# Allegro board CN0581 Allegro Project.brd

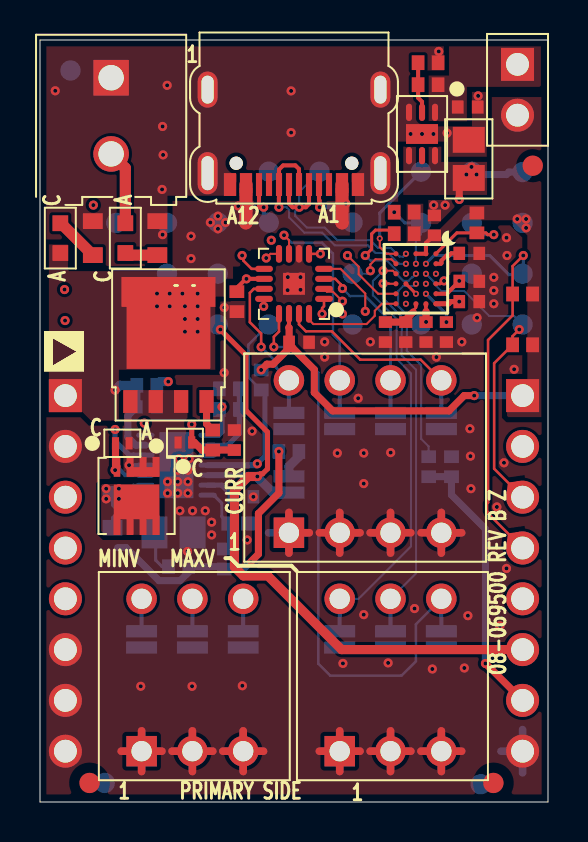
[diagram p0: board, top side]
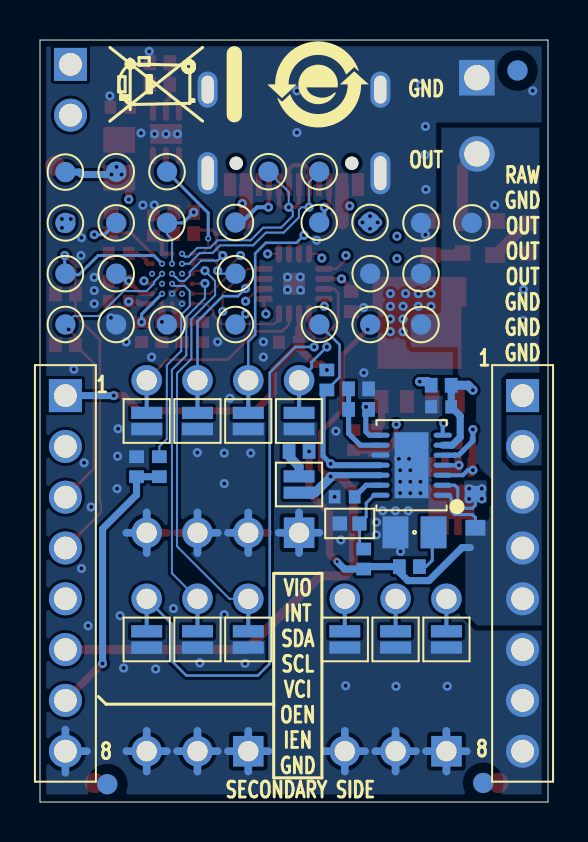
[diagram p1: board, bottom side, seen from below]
Outline 25.4 x 38.1 mm; copper layers: TOP, L2_GND, L3_SIG/PWR, BOTTOM. Coordinates in mm from the lower left corner of the outline.
Outline path: 0,38.1 0,0 25.4,0 25.4,38.1 0,38.1

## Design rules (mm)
constraint set DEFAULT: min track width 0.102

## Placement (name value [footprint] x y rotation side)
C1  100NF  [C0402]  5.34 19.76 180 bottom
C2  0.022uF  [C0402]  10.17 15.26 180 bottom
C3  4.7uF  [C0805H53]  21.44 32.16 90 top
C4  1uF  [C0402]  12.95 22.99 0 top
C5  6800pF  [C0402]  9.72 18.1 270 top
C6  4.7uF  [C0402]  21.39 34.75 180 top
C7  1uF  [C0402]  17.27 23.49 270 top
C8  1uF  [C0402]  18.29 23.49 270 top
C9  1uF  [C0402]  20.32 23.49 270 top
C10  1uF  [C0402]  21.46 27.43 0 top
C11  1uF  [C0402]  21.46 26.04 0 top
C12  22uF  [C0805H60]  6.68 13.48 180 bottom
C13  0.1UF  [C0402]  21.46 25.02 0 top
C15  0.1UF  [C0402]  19.3 23.49 270 top
C16  1uF  [C0402]  19.72 28.83 90 top
D1  BZT52B15LP-7B  [DFN2_1X0_6]  7.25 17.98 180 top
D2  BZT52B15LP-7B  [DFN2_1X0_6]  4.12 17.93 0 top
DS1  LTST-C193KGKT-5A  [LED0603H12]  1.02 28.19 270 top
DS2  LTST-C193KGKT-5A  [LED0603H12]  4.27 28.19 90 top
M1  12402012E212A  [M12402012E212A]  12.7 34.54 180 top
NOREF  -  []  11.43 85.73 0 top
NOREF#2  -  [unnamed#2]  2.48 0.95 0 top
NOREF#3  -  []  92.71 68.58 0 top
NOREF#4  -  []  25.4 0 90 top
NOREF#5  -  []  1.27 2.54 0 top
NOREF#6  -  []  -159.89 -89.83 0 top
NOREF#7  -  []  0 0 0 top
NOREF#8  -  []  -160.27 -77.77 0 top
NOREF#9  -  []  -164.71 -81.39 0 top
NOREF#10  -  [unnamed#2]  24.64 31.81 0 top
NOREF#11  -  []  0 38.1 0 top
NOREF#12  -  []  -153.98 -76.88 0 top
NOREF#13  -  []  0 0 0 top
NOREF#14  -  []  25.4 0 90 top
NOREF#15  -  []  0 38.1 0 top
NOREF#16  -  []  1.27 2.54 0 top
NOREF#17  -  [unnamed#2]  22.67 0.95 0 top
NOREF#18  -  []  -222.25 -146.05 0 top
NOREF#19  -  []  0 38.1 270 top
NOREF#20  -  []  25.4 0 0 top
NOREF#21  -  []  0 0 0 top
NOREF#22  -  []  25.4 38.1 180 top
NOREF#23  -  [unnamed#2]  22.03 0.89 180 bottom
NOREF#24  -  [unnamed#2]  3.24 0.95 180 bottom
NOREF#25  -  []  11.49 35.88 180 bottom
NOREF#26  -  []  15.37 35.69 90 bottom
NOREF#27  -  [unnamed#2]  1.52 36.58 180 bottom
P1  -  [JPSLD02]  5.08 8.13 90 bottom
P2  -  [JPSLD02]  7.62 8.13 90 bottom
P3  -  [JPSLD02]  10.16 8.13 90 bottom
P4  -  [JPSLD02]  14.99 8.13 90 bottom
P5  -  [JPSLD02]  17.53 8.13 90 bottom
P6  -  [JPSLD02]  20.07 8.13 90 bottom
P7  -  [JPSLD02]  12.45 19.05 90 bottom
P8  -  [JPSLD02]  14.99 19.05 90 bottom
P9  -  [JPSLD02]  17.53 19.05 90 bottom
P10  -  [JPSLD02]  20.07 19.05 90 bottom
P11  CTB0308/2  [CNCAMDENCTB0308_2]  3.56 36.21 270 top
P12  M20-9990846  [CNHDR1X8H335]  1.27 20.32 270 bottom
P13  -  [JPSLD02]  12.45 15.88 90 bottom
P14  M20-9990846  [CNHDR1X8H335]  24.13 20.32 270 bottom
P15  TSW-101-08-F-D  [CNHDR2X1H340]  23.88 36.88 180 top
Q1  PSMN4R2-80YSEX  [SOT1023]  6.42 22.75 0 top
Q2  BSZ019N03LSATMA1  [PG-TSDSON-8_A]  4.83 15.3 180 top
R1  2.15K  [R0402]  19.43 16.76 90 bottom
R2  49.9K  [R0402]  20.57 16.76 270 bottom
R3  124K  [R0402]  5.34 20.84 180 bottom
R4  57.6K  [R0402]  9.47 19.63 180 bottom
R5  0  [R0402]  19.41 35.86 180 top
R6  1.5K  [R0603]  2.64 28.19 90 top
R7  2.15K  [R0402]  19.41 36.97 180 top
R8  49.9K  [R0402]  9.84 25.02 90 top
R9  2.15K  [R0402]  24.13 25.4 0 top
R10  2.15K  [R0402]  24.13 22.86 0 top
R11  2.15K  [R0402]  18.21 29.49 0 top
R12  2.15K  [R0402]  18.21 28.41 0 top
R13  49.9K  [R0402]  21.84 28.96 90 top
R14  11K  [R0402]  9.47 20.66 0 bottom
R15  1.5K  [R0603]  5.87 28.19 90 top
R16  10  [R0402]  8.64 18.1 270 top
R17  100K  [R0402]  11.06 21.1 90 bottom
R18  95.3K  [R0402]  9.22 12.15 270 bottom
R19  5K  [R0402H33]  9.91 13.93 180 bottom
R20  0.007  [R0603]  3.63 14.56 270 bottom
R21  100K  [R0402]  12.45 17.53 180 bottom
R22  0.1  [R0402]  6.93 11.77 0 bottom
S1  DS01C-254-S-03BE  [SWTHL356W390H281]  5.08 2.54 0 top
S2  DS01C-254-S-03BE  [SWTHL356W390H281]  14.99 2.54 0 top
S3  DS01C-254-L-04BE  [SWTHL456W390H281]  12.45 13.46 0 top
TP1  TESTPAD  [TPSMC40]  24.13 31.5 180 bottom
TP2  TESTPAD  [TPSMC40]  8.9 28.98 180 bottom
TP3  TESTPAD  [TPSMC40]  6.35 23.88 180 bottom
TP4  TESTPAD  [TPSMC40]  3.81 28.96 180 bottom
TP5  TESTPAD  [TPSMC40]  15.63 28.98 180 bottom
TP6  TESTPAD  [TPSMC40]  11.44 28.98 180 bottom
TP7  TESTPAD  [TPSMC40]  13.98 31.52 180 bottom
TP8  TESTPAD  [TPSMC40]  11.44 31.52 180 bottom
TP9  TESTPAD  [TPSMC40]  6.35 26.42 180 bottom
TP10  TESTPAD  [TPSMC40]  6.35 28.96 180 bottom
TP11  TESTPAD  [TPSMC40]  8.89 26.42 180 bottom
TP12  TESTPAD  [TPSMC40]  21.59 31.52 180 bottom
TP13  TESTPAD  [TPSMC40]  24.13 28.96 180 bottom
TP14  TESTPAD  [TPSMC40]  24.13 26.42 180 bottom
TP15  TESTPAD  [TPSMC40]  24.13 23.88 180 bottom
TP16  TESTPAD  [TPSMC40]  21.59 26.42 180 bottom
TP17  TESTPAD  [TPSMC40]  21.59 28.96 180 bottom
TP18  TESTPAD  [TPSMC40]  21.59 23.88 180 bottom
TP19  TESTPAD  [TPSMC40]  8.89 23.88 180 bottom
TP20  TESTPAD  [TPSMC40]  11.43 23.88 180 bottom
TP21  TESTPAD  [TPSMC40]  19.05 31.52 180 bottom
TP22  TESTPAD  [TPSMC40]  15.63 26.42 180 bottom
TP23  TESTPAD  [TPSMC40]  19.05 28.96 180 bottom
TP24  TESTPAD  [TPSMC40]  15.63 23.88 180 bottom
TP25  TESTPAD  [TPSMC40]  19.05 23.88 180 bottom
U1  LTC4364HDE-2#PBF  [DFN14_4X3_PAD3_3X1_7]  6.82 16.84 90 bottom
U2  ADP7142ACPZN3.3  [DFN6_2X2_PAD1_6X1]  19.1 33.4 180 top
U3  MAX4701ETE+  [QFN16_3X3_PAD1_1X1_1]  12.7 25.91 90 top
U4  MAX77958EWV+  [WLCSP30H27]  18.8 26.16 180 top

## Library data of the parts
C1 = CAP: User Part Number: UPN; Tolerance: 10; alternate symbols: (C0402L); part number: CAP_SM-100NF,25V,10,E060176,C0402; tolerance: 10
C2 = CAP: User Part Number: UPN; Tolerance: 10; alternate symbols: (C0402L); part number: CAP_SM-0.022UF,25V,10,E042115,C0402; tolerance: 10
C3 = CAP: Tolerance: 10; User Part Number: UPN; alternate symbols: (); part number: CAP_SM-4.7UF,50V,10,E028468,C0805H53; tolerance: 10
C4 C7-C11 C16 = CAP: User Part Number: UPN; Tolerance: 10; alternate symbols: (C0402L); part number: CAP_SM-1UF,10V,10,E028140,C0402; tolerance: 10
C5 = CAP: User Part Number: UPN; Tolerance: 10; alternate symbols: (C0402L); part number: CAP_SM-6800PF,50V,10,E034944,C0402; tolerance: 10
C6 = CAP: User Part Number: UPN; Tolerance: 10; alternate symbols: (C0402L); part number: CAP_SM-4.7UF,6.3V,10,E020089,C0402; tolerance: 10
C12 = CAP: Tolerance: 20; User Part Number: UPN; alternate symbols: (); part number: CAP_SM-22UF,35V,20,E025497,C0805H60; tolerance: 20
C13 C15 = CAP: User Part Number: UPN; Tolerance: 10; alternate symbols: (C0402L); part number: CAP_SM-0.1UF,50V,10,E048331,C0402; tolerance: 10
D1 D2 = DIOZNR: Tolerance: 2; User Part Number: UPN; alternate symbols: (); part number: DIOZNR_SM-BZT52B15LP-7B,15V,2,E061558,DFN2_1X0_6; tolerance: 2
DS1 DS2 = DIOLED: User Part Number: UPN; Tolerance: N/A; alternate symbols: (); part number: DIOLED_SM-LTST-C193KGKT-5A,N/A,N/A,E020972,LED0603H12; tolerance: N/A
M1 = MODUSB16P_4PSHLD_V2: User Part Number: UPN; Tolerance: N/A; alternate symbols: (); part number: MODUSB16P_4PSHLD_V2_SM-12402012E212A,E055749,M12402012E212A; tolerance: N/A
P1-P10 P13 = NC2P: User Part Number: UPN; Tolerance: N/A; alternate symbols: (); part number: NC2P_SM-JPSLD02,E006230,JPSLD02; tolerance: N/A
P11 = CN2P: User Part Number: UPN; Tolerance: N/A; alternate symbols: (); part number: CN2P_TH-CTB0308/2,E026049,CNCAMDENCTB0308_2; tolerance: N/A
P12 P14 = CN8P_A: User Part Number: UPN; Tolerance: N/A; alternate symbols: (); part number: CN8P_A_TH-M20-9990846,E027673,CNHDR1X8H335; tolerance: N/A
P15 = CN2P: User Part Number: UPN; Tolerance: N/A; alternate symbols: (); part number: CN2P_TH-TSW-101-08-F-D,E023119,CNHDR2X1H340; tolerance: N/A
Q1 = TRANNMOSFET_V13: Tolerance: N/A; User Part Number: UPN; alternate symbols: (); part number: TRANNMOSFET_V13_SM-PSMN4R2-80YSEX,E061557,SOT1023; tolerance: N/A
Q2 = TRANNMOSFET8P: User Part Number: UPN; Tolerance: N/A; alternate symbols: (); part number: TRANNMOSFET8P_SM-BSZ019N03LSATMA1,E026048,PG-TSDSON-8_A; tolerance: N/A
R1 R7 R9-R12 = RES: User Part Number: UPN; Tolerance: 1; alternate symbols: (R0402L); part number: RES_SM-2.15K,E030383,1/10W,1,R0402; tolerance: 1
R2 R8 R13 = RES: User Part Number: UPN; Tolerance: 1; alternate symbols: (R0402L); part number: RES_SM-49.9K,E026957,1/16W,1,R0402; tolerance: 1
R3 = RES: User Part Number: UPN; Tolerance: 1; alternate symbols: (R0402L); part number: RES_SM-124K,E026070,1/16W,1,R0402; tolerance: 1
R4 = RES: User Part Number: UPN; Tolerance: 1; alternate symbols: (R0402L); part number: RES_SM-57.6K,E022063,1/16W,1,R0402; tolerance: 1
R5 = RES: User Part Number: UPN; Tolerance: JUMPER; alternate symbols: (R0402L); part number: RES_SM-0,E025232,1/16W,JUMPER,R0402; tolerance: JUMPER
R6 R15 = RES: User Part Number: UPN; Tolerance: 5; alternate symbols: (R0603L); part number: RES_SM-1.5K,E056769,1/4W,5,R0603; tolerance: 5
R14 = RES: User Part Number: UPN; Tolerance: 1; alternate symbols: (R0402L); part number: RES_SM-11K,E015614,1/10W,1,R0402; tolerance: 1
R16 = RES: User Part Number: UPN; Tolerance: 5; alternate symbols: (R0402L); part number: RES_SM-10,E042731,1/10W,5,R0402; tolerance: 5
R17 R21 = RES: User Part Number: UPN; Tolerance: 5; alternate symbols: (R0402L); part number: RES_SM-100K,E027220,1/16W,5,R0402; tolerance: 5
R18 = RES: User Part Number: UPN; Tolerance: 1; alternate symbols: (R0402L); part number: RES_SM-95.3K,E006343,1/10W,1,R0402; tolerance: 1
R19 = RES: Tolerance: 0.1; User Part Number: UPN; alternate symbols: (); part number: RES_SM-5K,E025964,1/20W,0.1,R0402H33; tolerance: 0.1
R20 = RES: User Part Number: UPN; Tolerance: 1; alternate symbols: (R0603L); part number: RES_SM-0.007,E061842,1/2W,1,R0603; tolerance: 1
R22 = RES: User Part Number: UPN; Tolerance: 1; alternate symbols: (R0402L); part number: RES_SM-0.1,E017078,1/6W,1,R0402; tolerance: 1
S1 S2 = SWSPST6PIN: User Part Number: UPN; Tolerance: N/A; alternate symbols: (); part number: SWSPST6PIN_TH-DS01C-254-S-03BE,E055746,SWTHL356W390H281; tolerance: N/A
S3 = SWSPST8P: User Part Number: UPN; Tolerance: N/A; alternate symbols: (); part number: SWSPST8P_TH-DS01C-254-L-04BE,E055747,SWTHL456W390H281; tolerance: N/A
TP1-TP25 = NCTESTPAD: Tolerance: N/A; User Part Number: UPN; alternate symbols: (); part number: NCTESTPAD_SM-TESTPAD,E019801,TPSMC40; tolerance: N/A
U1 = LINLTC4364_X: User Part Number: UPN; Tolerance: N/A; alternate symbols: (); part number: LINLTC4364_X_SM-LTC4364HDE-2#PBF,E031515,DFN14_4X3_PAD3_3X1_7; tolerance: N/A
U2 = ADP7142: User Part Number: UPN; Tolerance: N/A; alternate symbols: (); part number: ADP7142_SM-ADP7142ACPZN3.3,E023518,DFN6_2X2_PAD1_6X1; tolerance: N/A
U3 = ADMAX4XXX: User Part Number: UPN; Tolerance: N/A; alternate symbols: (); part number: ADMAX4XXX_SM-MAX4701ETE+,E055643,QFN16_3X3_PAD1_1X1_1; tolerance: N/A
U4 = ICMAX77958: User Part Number: UPN; Tolerance: N/A; alternate symbols: (); part number: ICMAX77958_SM-MAX77958EWV+,E045058,WLCSP30H27; tolerance: N/A

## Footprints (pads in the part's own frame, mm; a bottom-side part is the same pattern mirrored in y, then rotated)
C0402
  rect 0.584x0.66 smd: 1(-0.5,0) 2(0.5,0)
C0805H53
  rect 1.295x1.6 smd: 1(-0.953,0) 2(0.953,0)
C0805H60
  rect 1.295x1.6 smd: 1(-0.953,0) 2(0.953,0)
CNCAMDENCTB0308_2
  rect 1.778x1.778 hole 1.27: 1(0,0)
  round 1.778 hole 1.27: 2(3.81,0)
CNHDR1X8H335
  rect 1.651x1.651 hole 1.143: 1(0,0)
  round 1.651 hole 1.143: 2(2.54,0) 3(5.08,0) 4(7.62,0) 5(10.16,0) 6(12.7,0) 7(15.24,0) 8(17.78,0)
CNHDR2X1H340
  rect 1.651x1.651 hole 1.143: 1(0,0)
  round 1.651 hole 1.143: 2(0,2.54)
DFN2_1X0_6
  rect 0.356x0.61 smd: A(0.34,0) C(-0.34,0)
DFN6_2X2_PAD1_6X1
  oval 0.305x0.864 smd: 1(-0.65,-1.082) 2(0,-1.082) 3(0.65,-1.082) 4(0.65,1.082) 5(0,1.082) 6(-0.65,1.082)
  rect 1.6x0.991 smd: PAD(0,0)
DFN14_4X3_PAD3_3X1_7
  oval 0.254x0.914 smd: 1(-1.5,-1.557) 2(-1,-1.557) 3(-0.5,-1.557) 4(0,-1.557) 5(0.5,-1.557) 6(1,-1.557) 7(1.5,-1.557) 8(1.5,1.557) 9(1,1.557) 10(0.5,1.557) 11(0,1.557) 12(-0.5,1.557) 13(-1,1.557) 14(-1.5,1.557)
  rect 3.302x1.702 smd: PAD(0,0)
JPSLD02
  rect 0.61x1.549 smd: 1(-0.406,0) 2(0.406,0)
LED0603H12
  rect 0.787x0.787 smd: A(0.744,0) C(-0.744,0)
M12402012E212A
  round 0.66 hole 0.66 unplated: (-2.89,2.605) (2.89,2.605)
  rect 0.61x1.143 smd: A1(-3.2,3.67) A4(-2.4,3.67) A9(2.4,3.67) A12(3.2,3.67)
  rect 0.305x1.143 smd: A5(-1.25,3.67) A6(-0.25,3.67) A7(0.25,3.67) A8(1.25,3.67) B5(1.75,3.67) B6(0.75,3.67) B7(-0.75,3.67) B8(-1.75,3.67)
  round 0.127 smd: B1(3.2,3.97) B4(2.4,3.97) B9(-2.4,3.97) B12(-3.2,3.97)
  oval 0.991x2.108 hole 0.61x1.702: SH1(-4.32,3.105) SH4(4.32,3.105)
  oval 0.991x1.803 hole 0.61x1.397: SH2(-4.32,-1.075) SH3(4.32,-1.075)
PG-TSDSON-8_A
  rect 0.33x0.991 smd: 1(-0.975,-1.455) 2(-0.325,-1.455) 3(0.325,-1.455) 4(0.975,-1.455) 5(0.975,1.455) 6(0.325,1.455) 7(-0.325,1.455) 8(-0.975,1.455)
QFN16_3X3_PAD1_1X1_1
  oval 0.305x0.889 smd: 1(-0.75,-1.5) 2(-0.25,-1.5) 3(0.25,-1.5) 4(0.75,-1.5) 9(0.75,1.5) 10(0.25,1.5) 11(-0.25,1.5) 12(-0.75,1.5)
  oval 0.889x0.305 smd: 5(1.5,-0.75) 6(1.5,-0.25) 7(1.5,0.25) 8(1.5,0.75) 13(-1.5,0.75) 14(-1.5,0.25) 15(-1.5,-0.25) 16(-1.5,-0.75)
  rect 1.092x1.092 smd: PAD(0,0)
R0402
  rect 0.635x0.737 smd: 1(-0.5,0) 2(0.5,0)
R0402H33
  rect 0.711x0.711 smd: 1(-0.49,0) 2(0.49,0)
R0603
  rect 0.787x0.991 smd: 1(-0.85,0) 2(0.85,0)
SOT1023
  rect 0.711x1.143 smd: 1(-1.905,-2.728) 2(-0.635,-2.728) 3(0.635,-2.728) 4(1.905,-2.728)
  custom 1.149x1.149 smd: 5(0,1.201)
SWTHL356W390H281
  rect 1.524x1.524 hole 1.016: 1A(0,0)
  round 1.524 hole 1.016: 1B(0,7.62) 2A(2.54,0) 2B(2.54,7.62) 3A(5.08,0) 3B(5.08,7.62)
SWTHL456W390H281
  rect 1.524x1.524 hole 1.016: 1A(0,0)
  round 1.524 hole 1.016: 1B(0,7.62) 2A(2.54,0) 2B(2.54,7.62) 3A(5.08,0) 3B(5.08,7.62) 4A(7.62,0) 4B(7.62,7.62)
TPSMC40
  round 1.016 smd: 1(0,0)
unnamed#2
  round 1.016 smd: (0,0)
WLCSP30H27
  round 0.254 smd: A1(-1,-1.25) A2(-1,-0.75) A3(-1,-0.25) A4(-1,0.25) A5(-1,0.75) A6(-1,1.25) B1(-0.5,-1.25) B2(-0.5,-0.75) B3(-0.5,-0.25) B4(-0.5,0.25) B5(-0.5,0.75) B6(-0.5,1.25) C1(0,-1.25) C2(0,-0.75) C3(0,-0.25) C4(0,0.25) C5(0,0.75) C6(0,1.25) D1(0.5,-1.25) D2(0.5,-0.75) D3(0.5,-0.25) D4(0.5,0.25) D5(0.5,0.75) D6(0.5,1.25) E1(1,-1.25) E2(1,-0.75) E3(1,-0.25) E4(1,0.25) E5(1,0.75) E6(1,1.25)

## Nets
GND: C1.1 C2.1 C3.2(N2) C4.2(N2) C5.1 C6.1 C7.2(N2) C8.2(N2) C9.2(N2) C10.2(N2) C11.2(N2) C12.1 C13.2(N2) C15.2(N2) C16.2(N2) M1.A1 M1.A12 M1.B1 M1.B12 M1.SH1 M1.SH2 M1.SH3 M1.SH4 P1.1 P2.1 P3.1 P4.1 P5.1 P6.1 P7.1 P8.1 P9.1 P10.1 P11.1 P12.2 P12.6 P12.7 P12.8(N8) P14.8(N8) R2.1 R6.2(N2) R7.1 R8.1 R14.1 R15.2(N2) R19.1 S1.1A S1.2A S1.3A S2.1A S2.2A S2.3A S3.1A S3.2A S3.3A S3.4A TP9.1(N1) TP10.1(N1) TP11.1(N1) TP18.1(N1) U1.10 U1.PAD U2.3 U2.PAD U3.6 U3.PAD U4.C5 U4.D4 U4.D6
VBUS_OUT: DS2.A(P) P11.2(N2) P12.3 P12.4 P12.5 R18.2(N2) R20.2(N2) R21.2(N2) R22.2(N2) TP3.1(N1) TP4.1(N1) U1.1
VBUS_OUT_EN: R1.2(N2) U4.C4
DGATE: D2.C Q2.4 U1.3
DN_OUT: TP21.1(N1) U4.E1
DP_OUT: TP22.1(N1) U4.E2
ENOUT: P13.1 P14.6 TP19.1(N1) U1.12
FLT#: R17.1 TP20.1(N1) U1.11
HGATE: C5.2(N2) D1.C R16.2(N2) U1.5
MAXVBUS_SW1: P6.2(N2) S2.3B U3.13
MAXVBUS_SW2: P5.2(N2) S2.2B U4.E4
MAXVBUS_SW4: P4.2(N2) S2.1B(N6) U4.E3
MINVBUS_SW1: P3.2(N2) S1.3B U3.1
MINVBUS_SW2: P2.2(N2) S1.2B U3.5
MINVBUS_SW4: P1.2(N2) S1.1B(N6) U3.9
MSTR_SCL: R11.1 TP23.1(N1) U4.C2
MSTR_SDA: R12.1 TP24.1(N1) U4.C3
MUX_SEL: R8.2(N2) U3.2 U3.10 U4.D3
OPCURR_SW1: P10.2(N2) S3.4B U3.15
OPCURR_SW2: P9.2(N2) S3.3B U3.3
OPCURR_SW4: P8.2(N2) S3.2B U3.7
OPCURR_SW8: P7.2(N2) S3.1B(N8) U3.11
OV_IN: R4.1 R14.2(N2) U1.9
OV_OUT: R18.1 R19.2(N2) U1.14
PP1V8_LDO: C9.1 U4.B5
PP3V3_LDO: C6.2(N2) P15.1 R5.1 U2.1(VOUT)
PPVIO: C4.1 C16.1 P14.1 P15.2(N2) R9.2(N2) R10.2(N2) R11.2(N2) R12.2(N2) R13.2(N2) R17.2(N2) TP13.1(N1) U3.14(V+) U4.B1 U4.C1(VIO2)
PRG_VCIN: C11.1 P14.5 TP16.1(N1) U4.A5
SNS: Q2.5 Q2.6 Q2.7 Q2.8 R20.1 U1.2
SRC: D1.A(P) D2.A(P) Q1.1 Q1.2 Q1.3(S3) Q2.1 Q2.2 Q2.3(S3) U1.4
TMR: C2.2(N2) U1.13
UNNAMED_2_ADMAX4XXX_I2_COM1: U3.16 U4.E6
UNNAMED_2_ADMAX4XXX_I2_COM2: U3.4 U4.B4
UNNAMED_2_ADMAX4XXX_I2_COM3: U3.8 U4.E5
UNNAMED_2_ADMAX4XXX_I2_COM4: U3.12 U4.D5
UNNAMED_2_ADP7142_I10_SENSE: R5.2(N2) R7.2(N2) U2.2
UNNAMED_2_CAP_I45_N1: C7.1 C8.1 U4.C6
UNNAMED_2_CAP_I53_N1: C10.1 U4.A2
UNNAMED_2_CAP_I151_N2: C12.2(N2) R22.1
UNNAMED_2_DIOLED_I131_N: DS2.C R15.1
UNNAMED_2_DIOLED_I134_N: DS1.C R6.1
UNNAMED_2_NC2P_I185_N2: P13.2(N2) R21.1
UNNAMED_2_RES_I157_N1: Q1.4 R16.1
USB_CC1: M1.A5 TP5.1(N1) U4.A3
USB_CC2: M1.B5 TP6.1(N1) U4.A4
USB_DN: M1.A7 M1.B7 TP7.1(N1) U4.D1
USB_DP: M1.A6 M1.B6 TP8.1(N1) U4.D2
USB_VBUS_RAW: C1.2(N2) C3.1 C13.1 DS1.A(P) M1.A4 M1.A9 M1.B4 M1.B9(VBUS_4) P12.1 Q1.5 R3.2(N2) TP1.1(N1) TP2.1(N1) TP12.1(N1) U1.6(VCC) U2.4 U2.6 U4.A6
USR_INT#: P14.2 R13.1 TP17.1(N1) U4.A1
USR_OUT_EN: P14.7 R1.1 R2.2(N2) U1.7
USR_PPSYS: C15.1 TP25.1(N1) U4.B6
USR_SCL: P14.4 R9.1 TP14.1(N1) U4.B2
USR_SDA: P14.3 R10.1 TP15.1(N1) U4.B3
UV_IN: R3.1 R4.2(N2) U1.8

Pads without a net: M1 A8 B8; U2 5

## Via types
v1: diameter 0.457, hole 0.203, TOP to BOTTOM, 156 vias
v2: diameter 0.305, hole 0.152, TOP to BOTTOM, 16 vias

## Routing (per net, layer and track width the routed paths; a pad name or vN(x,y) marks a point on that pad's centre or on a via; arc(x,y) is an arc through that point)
GND: length 169
  TOP w0.152: U4.D4 v2(18.8,25.41)
  TOP w0.381: S3.1A 13.46,13.46 ; S3.1A 12.45,14.48 ; S3.1A 12.45,12.45 ; 13.97,2.54 S2.1A ; S2.1A 14.99,1.52 ; S2.1A 16,2.54 ; S2.1A 14.99,3.56 ; S3.3A 18.54,13.46 ; S3.3A 17.53,12.45 ; S3.3A 17.53,14.48 ; S3.3A 16.51,13.46 ; S1.2A 7.62,3.56 ; S1.2A 7.62,1.52 ; S1.2A 8.64,2.54 ; S1.2A 6.6,2.54 ; 16.51,2.54 S2.2A ; S2.2A 17.53,3.56 ; S2.2A 18.54,2.54 ; S2.2A 17.53,1.52 ; S1.1A 6.1,2.54 ; S1.1A 5.08,3.56 ; S1.1A 5.08,1.52 ; S1.1A 4.06,2.54 ; 14.99,12.45 S3.2A ; S3.2A 16,13.46 ; S3.2A 13.97,13.46 ; S3.2A 14.99,14.48 ; S2.3A 21.08,2.54 ; S2.3A 19.05,2.54 ; S2.3A 20.07,3.56 ; S2.3A 20.07,1.52 ; S3.4A 20.07,14.48 ; S3.4A 21.08,13.46 ; S3.4A 19.05,13.46 ; S3.4A 20.07,12.45 ; S1.3A 11.18,2.54 ; S1.3A 10.16,3.56 ; S1.3A 10.16,1.52 ; S1.3A 9.14,2.54
  L2_GND w0.381: S1.3A 11.18,2.54 ; S1.3A 10.16,3.56 ; S1.3A 10.16,1.52 ; S1.3A 9.14,2.54 ; S3.3A 18.54,13.46 ; S3.3A 17.53,12.45 ; S3.3A 16.51,13.46 ; S3.3A 17.53,14.48 ; 24.13,1.46 P14.8 ; P14.8 23.05,2.54 ; P14.8 24.13,3.62 ; 13.97,13.46 S3.2A ; S3.2A 14.99,12.45 ; S3.2A 14.99,14.48 ; S3.2A 16,13.46 ; S2.1A 14.99,3.56 ; S2.1A 14.99,1.52 ; S2.1A 13.97,2.54 ; S2.1A 16,2.54 ; 12.45,12.45 S3.1A ; S3.1A 11.43,13.46 ; S3.1A 13.46,13.46 ; S3.1A 12.45,14.48 ; S2.2A 17.53,3.56 ; S2.2A 17.53,1.52 ; S2.2A 16.51,2.54 ; S2.2A 18.54,2.54 ; S3.4A 21.08,13.46 ; S3.4A 20.07,12.45 ; S3.4A 20.07,14.48 ; S3.4A 19.05,13.46 ; 19.05,2.54 S2.3A ; S2.3A 21.08,2.54 ; S2.3A 20.07,1.52 ; S2.3A 20.07,3.56 ; S1.1A 6.1,2.54 ; S1.1A 5.08,3.56 ; S1.1A 4.06,2.54 ; S1.1A 5.08,1.52 ; 6.6,2.54 S1.2A ; S1.2A 7.62,1.52 ; S1.2A 8.64,2.54 ; S1.2A 7.62,3.56
  L3_SIG/PWR w0.381: S2.3A 21.08,2.54 ; S2.3A 20.07,1.52 ; S2.3A 20.07,3.56 ; S2.3A 19.05,2.54 ; 17.53,12.45 S3.3A ; S3.3A 18.54,13.46 ; S3.3A 17.53,14.48 ; S3.3A 16.51,13.46 ; 9.14,2.54 S1.3A ; S1.3A 10.16,3.56 ; S1.3A 10.16,1.52 ; S1.3A 11.18,2.54 ; S3.2A 14.99,14.48 ; S3.2A 13.97,13.46 ; S3.2A 16,13.46 ; S3.2A 14.99,12.45 ; S1.1A 6.1,2.54 ; S1.1A 5.08,3.56 ; S1.1A 5.08,1.52 ; S1.1A 4.06,2.54 ; 11.43,13.46 S3.1A ; S3.1A 12.45,14.48 ; S3.1A 12.45,12.45 ; S3.1A 13.46,13.46 ; 16.51,2.54 S2.2A ; S2.2A 17.53,3.56 ; S2.2A 18.54,2.54 ; S2.2A 17.53,1.52 ; 14.99,1.52 S2.1A ; S2.1A 13.97,2.54 ; S2.1A 14.99,3.56 ; S2.1A 16,2.54 ; 24.13,1.46 P14.8 ; P14.8 23.05,2.54 ; P14.8 24.13,3.62 ; 20.07,12.45 S3.4A ; S3.4A 21.08,13.46 ; S3.4A 19.05,13.46 ; S3.4A 20.07,14.48 ; 7.62,1.52 S1.2A ; S1.2A 6.6,2.54 ; S1.2A 7.62,3.56 ; S1.2A 8.64,2.54
  BOTTOM w0.381: S1.3A 10.16,3.56 ; S1.3A 10.16,1.52 ; S1.3A 11.18,2.54 ; S1.3A 9.14,2.54 ; S3.2A 16,13.46 ; S3.2A 14.99,12.45 ; S3.2A 14.99,14.48 ; 17.53,1.52 S2.2A ; S2.2A 16.51,2.54 ; S2.2A 17.53,3.56 ; S2.2A 18.54,2.54 ; 7.62,1.52 S1.2A ; S1.2A 8.64,2.54 ; S1.2A 6.6,2.54 ; S1.2A 7.62,3.56 ; 16.51,13.46 S3.3A ; S3.3A 17.53,14.48 ; S3.3A 17.53,12.45 ; 13.97,2.54 S2.1A ; S2.1A 14.99,3.56 ; S2.1A 16,2.54 ; S2.1A 14.99,1.52 ; 20.07,1.52 S2.3A ; S2.3A 20.07,3.56 ; S2.3A 21.08,2.54 ; S2.3A 19.05,2.54 ; 24.13,1.46 P14.8 ; P14.8 23.05,2.54 ; P14.8 24.13,3.62 ; 4.06,2.54 S1.1A ; S1.1A 6.1,2.54 ; S1.1A 5.08,1.52 ; S1.1A 5.08,3.56 ; 12.45,12.45 S3.1A ; S3.1A 13.46,13.46 ; S3.1A 11.43,13.46 ; S3.1A 12.45,14.48 ; S3.4A 20.07,14.48 ; S3.4A 21.08,13.46 ; S3.4A 20.07,12.45
  vias: v1(0.76,35.56) v1(5.04,5.79) v1(6.1,30.63) v1(6.13,33.78) v1(6.15,32.35) v1(6.13,28.37) v1(6.36,35.83) v1(6.38,16.01) v1(6.38,15.44) v1(6.89,16.59) v1(6.89,16.01) v1(6.89,15.44) v1(6.95,17.16) v1(6.99,14.56) v1(7.39,16.59) v1(7.39,16.01) v1(7.39,15.44) v1(7.37,12.53) v1(7.46,17.16) v1(7.6,5.79) v1(7.63,14.56) v1(8.26,14.56) v1(8.58,13.99) v1(8.58,13.36) v1(9.22,24.72) v1(9.21,21.46) v1(10.12,5.81) v1(10.36,13.1) v1(10.6,18.54) v1(10.67,15.26) v1(11.56,28.09) v1(12.39,26.25) v1(12.38,25.59) v1(12.56,35.55) v1(12.56,33.47) v1(13.03,26.25) v1(13.03,25.61) v1(14.23,23.01) v1(14.23,22.25) v1(14.87,17.44) v1(15.15,6.93) v1(15.91,20.19) v1(16.19,17.44) v1(16.19,15.92) v1(16.19,9.37) v1(16.52,23.01) v1(17.41,6.95) v1(17.53,17.47) v1(18.53,33.4) v1(18.73,9.67) v1(19.1,33.4) v1(19.62,6.65) v1(19.67,33.4) v1(19.68,29.84) v1(19.82,22.25) v1(19.94,37.53) v1(20.26,29.84) v1(20.35,33.45) v1(21.09,23.01) v1(21.22,6.7) v1(21.39,9.32) v1(21.5,18.66) v1(21.52,17.29) v1(21.55,15.67) v1(21.91,35.31) v1(21.85,24.21) v1(22.69,26.23) v1(22.69,25.57) v1(22.69,24.91) v1(22.84,14.75) v1(22.99,8.81) v1(23.2,16.96) v1(23.33,28.21) v1(23.35,27.33) v1(23.33,11.68) v1(23.71,21.64) v2(18.3,24.91)
VBUS_OUT: length 20.8
  TOP w0.356: v1(11.95,17.53) 11.95,15.45 10.92,14.43 10.92,12.39 v2(10.55,12.02)
  TOP w0.559: DS2.A 4.27,31.69 P11.2
  BOTTOM w0.152: R20.2 3.63,14.22 3.78,14.37 4.68,14.37 4.83,14.52 4.83,15.19 4.99,15.34 U1.1
  BOTTOM w0.356: 3.88,12.72 4.3,12.72 5.95,11.07 7.01,11.07 7.43,11.49 R22.2 9.1,11.77 R18.2 10.18,11.65 v2(10.55,12.02)
  vias: v1(1.23,25.62) v1(1.25,24.07) v1(2.67,29.84)
VBUS_OUT_EN: length 9.9
  BOTTOM w0.102: v2(18.8,25.91) 18.69,25.8 18.17,25.8 17.91,25.55 17.91,24.79 18.34,24.36 18.34,22.56 19.06,21.84 19.06,18.15 19.43,17.78 R1.2
DGATE: length 2.8
  TOP w0.356: D2.C 3.78,16.83 Q2.4
  BOTTOM w0.203: v1(3.75,16.59) 4.01,16.59 4.26,16.34 U1.3
DN_OUT: length 5.6
  TOP w0.102: U4.E1 17.32,27.41 16.99,27.74 v2(16.99,28.18)
  BOTTOM w0.152: TP21.1 16.99,29.45 v2(16.99,28.18)
DP_OUT: length 2.7
  TOP w0.102: U4.E2 17.57,27.13 16.77,27.13 16.52,26.88 v1(16.52,26.56)
  BOTTOM w0.102: v1(16.52,26.56) 16.37,26.42 TP22.1
ENOUT: length 34.4
  TOP w0.254: v1(10.87,16.28) 10.99,16.4 11.12,16.4 11.37,16.66 11.37,18.5 10.29,19.58 10.29,22.34 v1(9.02,23.62)
  TOP w0.457: P14.6 15.08,7.62 11.39,11.3 10.17,11.3 9.72,11.75 9.72,15.58 10.42,16.28 v1(10.87,16.28)
  BOTTOM w0.305: U1.12 10.8,16.34 v1(10.87,16.28)
  BOTTOM w0.457: v1(10.87,16.28) 10.87,16.24 11.64,15.47 P13.1
FLT#: length 10.4
  BOTTOM w0.127: TP20.1 10.42,22.87 10.42,21.24 R17.1
  BOTTOM w0.254: v1(10.87,16.91) 11.25,17.29 11.25,20.41 R17.1
  BOTTOM w0.305: v1(10.87,16.91) 10.79,16.84 U1.11
HGATE: length 10
  TOP w0.254: v1(7.59,18.88) D1.C
  TOP w0.356: D1.C 7.72,17.98 8.1,17.6 R16.2 C5.2
  L2_GND w0.254: v1(7.59,18.88) 7.02,19.45 4.58,19.45 v1(3.75,18.63)
  BOTTOM w0.254: v1(3.75,18.63) 3.75,18.05 4.46,17.35 4.66,17.35 4.67,17.34 U1.5
MAXVBUS_SW1: length 29.8
  TOP w0.127: U3.13 11.95,23.52 11.69,23.26 v1(11.69,22.75)
  BOTTOM w0.127: v1(11.69,22.75) 12.63,22.75 13.91,21.47 13.91,6.91 14.5,6.32 18.08,6.32 18.8,7.04 18.8,8.89 S2.3B
  BOTTOM w0.203: P6.2 S2.3B
MAXVBUS_SW2: length 19.3
  TOP w0.102: U4.E4 17.45,25.91 17.43,25.93 v1(17.15,25.93)
  BOTTOM w0.102: S2.2B 18.8,11.44 18.8,21.61 18.08,22.33 18.08,24.26 17.15,25.19 v1(17.15,25.93)
  BOTTOM w0.203: P5.2 S2.2B
MAXVBUS_SW4: length 21.8
  TOP w0.102: U4.E3 17.64,26.56 v1(17.15,26.56)
  BOTTOM w0.102: S2.1B 15.93,10.16 18.55,12.78 18.55,21.43 17.83,22.15 17.83,24.15 16.64,25.34 16.64,26.06 v1(17.15,26.56)
  BOTTOM w0.203: P4.2 S2.1B
MINVBUS_SW1: length 22.1
  TOP w0.127: U3.1 14.2,24.79 14.1,24.7 v1(14.1,24.4)
  L3_SIG/PWR w0.102: v1(14.1,24.4) 12.45,24.4 11.25,25.61 10.93,25.61 10.22,24.9 10.22,19.18 10.1,19.05 10.1,13.46 9.91,13.27 9.91,11.73 10.16,11.48 S1.3B
  BOTTOM w0.203: P3.2 S1.3B
MINVBUS_SW2: length 24.3
  TOP w0.127: U3.5 v1(14.02,27.41)
  L3_SIG/PWR w0.102: v1(14.02,27.41) 13.78,27.64 11.06,27.64 9.84,26.43 9.84,25.91 9.97,25.78 9.97,19.28 9.84,19.16 9.84,13.59 7.62,11.37 S1.2B
  BOTTOM w0.203: P2.2 S1.2B
MINVBUS_SW4: length 23
  TOP w0.127: v1(10.1,27.33) 10.17,27.26 10.17,27.07 10.58,26.66 U3.9
  L3_SIG/PWR w0.102: v1(10.1,27.33) 9.53,26.75 9.53,25.81 9.66,25.67 9.66,19.33 9.59,19.26 9.59,13.72 7.58,11.7 6.62,11.7 S1.1B
  BOTTOM w0.203: P1.2 S1.1B
MSTR_SCL: length 3.7
  BOTTOM w0.102: TP23.1 19.05,28.38 18.8,28.13 v2(18.8,26.91)
  BOTTOM w0.152: v1(17.71,29.49) 18.25,28.96 TP23.1
MSTR_SDA: length 11.1
  TOP w0.152: R12.1 17.53,28.6 16.77,28.6 16.58,28.4 16.58,27.64 v1(16.26,27.33)
  L3_SIG/PWR w0.102: v1(15.12,24.4) 15.95,25.23 17.61,25.23 v2(18.8,26.41)
  BOTTOM w0.102: v1(16.26,27.33) 16.52,27.07 17.34,27.07 17.91,26.5 17.91,26.31 18.17,26.06 18.42,26.06 18.61,26.25 18.63,26.25 v2(18.8,26.41) ; TP24.1 15.12,24.38 v1(15.12,24.4)
MUX_SEL: length 11.9
  TOP w0.102: v2(18.3,26.41) 18.29,26.41 ; v1(15.12,25.04) 14.65,25.51 14.34,25.51 U3.2
  TOP w0.203: R8.2 9.91,25.58 9.91,25.77 10.31,26.17 v1(10.32,26.16) U3.10
  L3_SIG/PWR w0.102: v2(18.3,26.41) 17.37,25.48 15.57,25.48 v1(15.12,25.04) 12.26,25.04 11.14,26.16 v1(10.32,26.16)
OPCURR_SW1: length 10.4
  TOP w0.127: U3.15 12.95,23.88 13.3,23.53 14.59,23.53 16.01,22.12 19.03,22.12 S3.4B
  BOTTOM w0.203: S3.4B P10.2
OPCURR_SW2: length 8.9
  TOP w0.127: U3.3 14.76,26.16 15.04,25.88 15.04,25.75 v1(15.12,25.67)
  BOTTOM w0.127: v1(15.12,25.67) 15.5,25.29 16.26,25.29 17.53,24.03 S3.3B
  BOTTOM w0.203: P9.2 S3.3B
OPCURR_SW4: length 12
  TOP w0.102: v1(12.2,28.34) 12.45,28.09 U3.7
  BOTTOM w0.127: S3.2B 14.99,23.01 14.64,23.36 14.64,27.42 14.1,27.96 12.58,27.96 v1(12.2,28.34)
  BOTTOM w0.203: P8.2 S3.2B
OPCURR_SW8: length 7.6
  TOP w0.127: U3.11 10.69,25.66 10.49,25.46 10.49,23.99 11.06,23.42 v1(11.06,22.75)
  BOTTOM w0.127: v1(11.06,22.75) 11.82,21.99 11.82,21.71 S3.1B
  BOTTOM w0.203: P7.2 S3.1B
OV_IN: length 4.1
  BOTTOM w0.254: U1.9 9.38,17.84 9.97,18.43 R4.1 R14.2
OV_OUT: length 3.4
  BOTTOM w0.152: U1.14 8.69,15.34 9.09,14.94 9.09,14.26 R19.2 9.42,12.86 R18.1
PP1V8_LDO: length 1.8
  BOTTOM w0.152: v1(20.32,24) 20.32,24.39 v2(19.3,25.41)
PPVIO: length 19.5
  TOP w0.203: 12.44,23.72 12.44,23.85 12.45,23.86 U3.14 ; U4.C1 U4.B1 19.3,27.94 19.68,28.33 C16.1
  TOP w0.356: 12.64,22.69 13.72,21.62 13.72,20.47 14.63,19.56 20.45,19.56 21.21,20.32 v1(21.71,20.32) ; 12.64,22.69 12.45,22.88 ; 12.64,22.69 12.45,22.69 ; 12.45,22.88 C4.1 12.45,23.71 12.44,23.72 ; 12.45,22.88 12.45,22.69 ; v1(11.06,21.6) 11.34,21.89 11.65,21.89 12.45,22.69
  BOTTOM w0.356: 23.92,29.15 v1(23.86,29.15) ; v1(21.71,20.32) P14.1
  vias: v1(24.3,29.15) v1(24.3,28.71)
PRG_VCIN: length 20.9
  TOP w0.203: U4.A5 20.34,25.41 C11.1
  TOP w0.356: C11.1 v1(20.96,26.06)
  L3_SIG/PWR w0.254: v1(20.96,26.06) 20.4,25.5 20.4,24.71 22.23,22.88 22.23,10.41 22.49,10.16 P14.5
  BOTTOM w0.152: v1(20.96,26.06) 21.09,26.06 21.45,26.42 TP16.1
SNS: length 3.2
  BOTTOM w0.152: R20.1 3.63,14.84 3.78,14.69 4.33,14.69 4.52,14.88 4.52,15.69 4.67,15.84 U1.2
  vias: v1(3.31,15.67) v1(3.31,15.16) v1(3.94,15.67) v1(3.94,15.16)
SRC: length 0.8
  BOTTOM w0.203: v1(4.45,16.84) U1.4
TMR: length 1.5
  BOTTOM w0.254: U1.13 9.09,15.84 C2.2
UNNAMED_2_ADMAX4XXX_I2_COM1: length 5.3
  TOP w0.102: U4.E6 17.09,24.91 16.74,24.56 16.74,24.31 16.33,23.9 13.67,23.9 13.45,24.12 U3.16
UNNAMED_2_ADMAX4XXX_I2_COM2: length 8.4
  TOP w0.102: U3.4 15.03,26.66 16.26,25.42 v1(16.26,24.53)
  L3_SIG/PWR w0.102: v2(19.3,25.91) 19.69,25.52 19.69,25.04 18.93,24.28 16.52,24.28 v1(16.26,24.53)
UNNAMED_2_ADMAX4XXX_I2_COM3: length 8.6
  TOP w0.102: U4.E5 16.91,25.41 15.93,26.39 15.93,26.77 v1(15.37,27.33) ; v1(11.31,27.2) 11.52,27.41 U3.8
  L3_SIG/PWR w0.102: v1(15.37,27.33) 14.87,26.82 11.69,26.82 v1(11.31,27.2)
UNNAMED_2_ADMAX4XXX_I2_COM4: length 8.6
  TOP w0.102: v1(11.18,24.79) 11.2,24.8 U3.12
  L3_SIG/PWR w0.102: v1(11.18,24.79) 12.07,23.9 15.25,23.9 15.63,24.28 15.63,24.53 16.07,24.98 17.85,24.98 18.14,25.27 18.15,25.27 v2(18.3,25.41)
UNNAMED_2_ADP7142_I10_SENSE: length 2.6
  TOP w0.203: R7.2 R5.2 18.91,35.21 19.1,35.01 U2.2
UNNAMED_2_CAP_I45_N1: length 2.1
  TOP w0.127: 18.66,24.5 18.66,24.57 18.8,24.71 U4.C6
  TOP w0.356: 18.66,24.5 18.29,24.13 C8.1 C7.1
UNNAMED_2_CAP_I53_N1: length 1.5
  TOP w0.203: U4.A2 20.04,26.91 20.07,26.94 20.07,27.07 20.33,27.33 20.45,27.33 20.56,27.43 C10.1
UNNAMED_2_CAP_I151_N2: length 2.2
  BOTTOM w0.152: R22.1 6.1,11.77 5.79,12.09 5.79,13.42 C12.2
UNNAMED_2_DIOLED_I131_N: length 1.6
  TOP w0.559: R15.1 4.37,27.34 DS2.C
UNNAMED_2_DIOLED_I134_N: length 2.3
  TOP w0.559: DS1.C 1.05,28.94 R6.1
UNNAMED_2_NC2P_I185_N2: length 1.5
  BOTTOM w0.457: R21.1 12.95,17.28 12.45,16.78 P13.2
UNNAMED_2_RES_I157_N1: length 1.6
  TOP w0.356: Q1.4 8.33,18.91 R16.1
USB_CC1: length 10.8
  TOP w0.203: M1.A5 13.95,30.1 13.98,30.07 v1(13.98,29.74)
  L3_SIG/PWR w0.152: v2(19.8,26.41) 19.8,27.29 18.49,28.6 17.47,28.6 17.25,28.82 14.9,28.82 v1(13.98,29.74)
  BOTTOM w0.203: TP5.1 15.31,28.98 14.55,29.74 v1(13.98,29.74)
USB_CC2: length 15
  TOP w0.152: v1(20.2,26.06) 20.14,26.06 20,25.91 U4.A4
  TOP w0.203: v1(11.18,29.74) 10.95,29.74 M1.B5
  L3_SIG/PWR w0.152: v1(11.18,29.74) 11.18,30.25 11.5,30.56 13.98,30.56 15.37,29.17 17.34,29.17 17.6,28.91 18.68,28.91 20.2,27.39 v1(20.2,26.06)
  BOTTOM w0.203: v1(11.18,29.74) 11.18,29.23 TP6.1
USB_DN: length 12.2
  TOP w0.203: M1.A7 12.45,29.92 12.63,29.74 v1(12.96,29.74) 13.29,29.74 13.45,29.9 M1.B7
  BOTTOM w0.102: v2(18.3,27.41) 18.15,27.27 17.97,27.27 17.53,27.71 16.9,27.71 16.52,28.09 14.87,28.09 14.23,28.72 13.34,28.72 12.76,29.3 12.76,29.54 v1(12.96,29.74) 12.96,30.5 TP7.1
USB_DP: length 13.6
  TOP w0.203: v1(11.95,29.74) 11.95,30.2 11.95,30.2 M1.B6 11.95,31.62 12.16,31.83 12.77,31.83 12.95,31.65 M1.A6
  BOTTOM w0.102: v2(18.3,26.91) 17.95,26.91 17.41,27.45 16.77,27.45 16.39,27.83 14.74,27.83 14.1,28.47 13.22,28.47 12.45,29.23 12.45,29.61 12.33,29.74 v1(11.95,29.74) 11.95,31.01 TP8.1
USB_VBUS_RAW: length 20.6
  TOP w0.102: 20.96,24.98 v1(20.96,25.02)
  TOP w0.254: U4.A6 20.44,24.91 20.54,25.02 v1(20.96,25.02)
  TOP w0.356: C3.1 20.96,30.73 v1(20.96,30.13)
  TOP w0.559: 10.29,28.96 10.29,29.59 10.3,29.6 ; 15.1,29.6 15.11,29.59 15.11,28.96
  TOP w0.66: M1.A4 M1.B9 15.1,28.97 15.11,28.96 ; 10.29,28.96 10.3,28.97 M1.B4 M1.A9
  L3_SIG/PWR w0.559: v1(20.96,25.02) 21.62,25.68 21.62,30.22 21.6,30.25
  BOTTOM w0.356: v1(21.83,31.37) 23.32,31.37 23.44,31.5 TP1.1 ; U1.6 4.79,17.84 4.39,18.24 4.39,19.3 C1.2 R3.2
  BOTTOM w0.457: v1(3.75,20.59) 4,20.84 R3.2
  vias: v1(5.85,25.42) v1(5.85,24.79) v1(6.48,25.42) v1(6.48,24.79) v1(7.12,25.42) v1(7.25,24.79) v1(7.25,24.15) v1(7.25,23.52) v1(7.55,28.29) v1(7.55,27.17) v1(7.88,25.42) v1(7.88,24.79) v1(7.88,24.15) v1(7.88,23.52) v1(8.52,28.98) v1(8.9,29.29) v1(8.9,28.66) v1(9.28,28.98) v1(9.91,29.8) v1(15.29,29.92) v1(21.32,31.37) v1(21.57,31.75)
USR_INT#: length 16.2
  TOP w0.152: v1(22.69,28.37) 22.39,28.37 22.3,28.46 R13.1 20.84,28.46 U4.A1
  L3_SIG/PWR w0.254: P14.2 23.49,18.42 22.97,18.94 22.97,24.38 23.4,24.81 23.4,26.54 22.69,27.25 v1(22.69,28.37)
  BOTTOM w0.152: TP17.1 22.18,28.37 v1(22.69,28.37)
USR_OUT_EN: length 46.7
  TOP w0.356: v1(22.27,6.93) 22.54,6.66 22.55,6.66 P14.7
  L3_SIG/PWR w0.356: v1(5.21,18.94) 5.6,18.56 5.6,13.67 3.99,12.06 3.99,9.5 5.53,7.96 10.49,7.96 13.36,5.08 P14.7
  BOTTOM w0.203: v1(5.21,18.94) 5.27,18.89 U1.7
  BOTTOM w0.356: v1(22.27,6.93) 22.27,13.66 20.57,15.36 R2.2 R1.1
USR_PPSYS: length 1
  TOP w0.127: C15.1 19.34,24 ; 19.3,24.53 19.3,24.54 U4.B6
  TOP w0.356: C15.1 v1(19.3,24) 19.3,24.53
USR_SCL: length 22.5
  TOP w0.127: v1(24.16,27.33) 23.63,26.79 R9.1 23.63,24.33 22.4,23.1 22.4,14.97 22.35,14.92 22.35,14.54 22.4,14.49 22.4,14.43 P14.4
  BOTTOM w0.152: v1(24.16,27.33) 24.16,26.45 TP14.1 24.08,26.37 23.45,26.37 22.49,27.33 19.71,27.33 v2(19.3,26.91)
USR_SDA: length 15.4
  TOP w0.127: v1(23.96,23.63) 23.63,23.29 R10.1 22.71,21.94 22.71,16.66 P14.3
  BOTTOM w0.102: TP15.1 23.71,24.3 22.47,24.3 21.22,25.55 20.07,25.55 19.69,25.93 19.69,26.02 v2(19.3,26.41)
UV_IN: length 5.8
  L3_SIG/PWR w0.457: v1(9.1,19.76) 8.66,19.76 7.39,21.02 v1(6.41,21.02)
  BOTTOM w0.254: U1.8 8.93,18.34 9.11,18.52 9.11,19.49 R4.2
  BOTTOM w0.457: v1(6.41,21.02) 6.03,21.02 R3.1

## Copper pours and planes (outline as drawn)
GND on TOP: 0.32,37.78 25.08,37.78 25.08,0.38 0.32,0.38 ; 1 cut-out
GND on BOTTOM: 0.32,37.78 25.08,37.78 25.08,0.38 0.32,0.38
GND on L2_GND: 0.64,0.64 0.64,1.4 0.32,1.4 0.32,37.72 25.08,37.72 25.08,1.52 24.64,1.52 24.64,0.64
GND on L3_SIG/PWR: 0.32,37.72 25.08,37.72 25.08,0.32 0.32,0.32
VBUS_OUT on BOTTOM: 0.43,33.72 5.33,33.72 5.33,25.29 5.34,25.29 5.34,24.54 5.47,24.4 6.61,24.4 6.87,24.15 6.87,22.86 6.74,22.74 4.51,22.74 4.51,21.4 3.6,20.49 3.6,16.88 2.93,16.21 2.93,14.18 3.06,14.05 4.07,14.05 4.14,13.99 4.14,9.42 3.54,8.83 0.32,8.83 0.32,16.57 1.83,16.58 2.33,17.08 2.33,21.15 2.02,21.47 0.43,21.47 0.43,21.89
VBUS_OUT on L3_SIG/PWR: 0.32,8.83 3.54,8.83 3.54,14.1 3.55,14.11 5.34,14.11 5.34,19.44 5.33,19.44 5.33,33.72 0.43,33.72 0.43,21.47 2.02,21.47 2.33,21.15 2.33,17.08 1.82,16.57 0.32,16.57
PP3V3_LDO on TOP: 19.43,34.04 21.34,34.04 21.34,35.76 24.98,35.76 25.04,35.83 25.04,37.78 20.45,37.78 20.45,36.32 19.43,36.32
PPVIO on TOP: 22.59,35.25 25.07,35.25 25.07,32.52 24.86,32.61 24.64,32.64 23.81,31.81 24.64,30.99 24.86,31.02 25.07,31.11 25.07,19.24 23.42,19.24 23.35,19.31 23.35,21.15 24.24,21.15 24.3,21.09 24.37,21.15 24.37,28.33 23.61,29.09 21.13,29.09 19.99,27.94 18.34,27.94 18.34,29.91 19.16,29.91 19.16,28.64 19.99,28.64 21.19,29.85 22.59,29.85
SNS on TOP (solid shape): 5.97,13.35 5.64,13.35 5.64,14.14 5.32,14.14 5.32,13.35 4.99,13.35 4.99,14.14 4.67,14.14 4.67,13.35 4.34,13.35 4.34,14.14 4.02,14.14 4.02,13.35 3.69,13.35 3.69,15.87 5.97,15.87
SNS on TOP: 5.98,15.9 3.12,15.9 3.06,15.83 3.06,13.55 3.25,13.36 5.98,13.36
SNS on BOTTOM: 4.2,16.02 4.2,15.01 4.14,14.94 3.12,14.94 3.06,15.01 3.06,16.02 3.12,16.09 4.14,16.09
SRC on TOP (solid shape): 4.67,16.75 4.99,16.75 4.99,17.25 5.32,17.25 5.32,16.75 5.64,16.75 5.64,17.25 5.97,17.25 5.97,16.26 4.34,16.26 4.34,17.25 4.67,17.25
SRC on TOP: 4.14,20.59 7.37,20.59 7.37,17.61 7.25,17.48 6.68,17.48 6.55,17.36 6.55,16.53 4.14,16.53
USB_VBUS_RAW on TOP: 15.49,30.06 15.49,28.32 11.58,28.32 11.58,27.64 10.57,27.64 10.57,26.77 9.65,26.77 9.65,26.16 9.27,26.16 9.27,25.27 8.76,25.27 8.76,21.61 3.94,21.61 3.94,19.07 2.55,19.07 2.1,19.51 2.1,19.51 2.1,19.49 0.44,19.49 0.44,27.88 1.4,27.88 1.4,26.61 1.46,26.54 6.63,26.54 6.63,30.06
USB_VBUS_RAW on TOP: 18.16,30.35 18.16,32.77 18.8,32.77 18.8,31.75 19.43,31.75 19.43,32.77 20.07,32.77 20.07,32 22.35,32 22.35,30.35
USB_VBUS_RAW on L3_SIG/PWR: 9.68,26.85 9.65,26.82 9.65,26.16 9.27,26.16 9.27,25.27 8.76,25.27 8.76,20.83 5.51,20.83 5.51,26.54 6.63,26.54 6.63,34.58 6.87,34.82 21.85,34.82 22.11,34.56 22.11,29.67 21.85,29.42 15.25,29.42 13.85,30.82 10.55,30.82 10.17,30.44 10.17,27.83 9.68,27.34

Small or netless copper shapes (teardrops, artwork): 4 on TOP

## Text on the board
Ref Des/Silkscreen Bottom: RAW | GND | OUT | SECONDARY SIDE | VIO | INT | SDA | SCL | VCI | OEN | IEN
Ref Des/Assembly Top: WIRE_ENTRY
Ref Des/Silkscreen Top: C | MINV | A | MAXV | PRIMARY SIDE | CURR | 08-069500 REV B Z
PAGE_OUTLINE: NA | B | ECR-113805 | 25MAY23 | V. BELECA | CUSTOMER EVALUATION Z
DIMENSION: LABEL PLACEMENT INFORMATION | HALF SIZE LABELS ARE | AVAILABLE IN THE LIBRARY | PLACE WHEELIE BIN LOGO | TO SUIT THE LAYOUT. | PLACE ROHS COMPLIANT LOGO | TO SUIT THE LAYOUT OR | DELETE IF NOT REQ'D. | PLACE CHINA ROHS COMPLIANT | LOGO TO SUIT THE LAYOUT OR | " " | 1.THE BOARD SIZE CAN BE ADJUSTED TO SUIT THE APPLICATION. | 2.THE MOUNTING HOLES CAN BE MOVED/REMOVED TO SUIT THE APPLICATION. | 3.THE FIDUCIALS CAN BE MOVED TO SUIT THE APPLICATION. | 4.ADJUST THE DIMENSIONS TO SUIT THE APPLICATION. | 5.ADD THE CORRECT LAYER STACKUP ON FAB2 BASED ON THE NO OF LAYERS ON THE PCB. | 6.THE ROHS COMPLIANT AND WHEELIE BIN LOGO'S CAN BE MOVED TO THE DESIRED LOCATION. | HALF SIZE VERSIONS OF THE LABELS ARE AVAILABLE IN THE LIBRARY. | NOTES FOR TEMPLATE USAGE. | (REF) | DIA MAX | SEE NOTE 15 | GENERIC D-SIZE TEMPLATE BR-067706A
User.11: C | A
User.15: PRIMARY SILKSCREEN | PRIMARY SOLDER MASK | PRIMARY SIDE   (LAYER 1) | L2_GND PLANE   (LAYER 2) | L3_SIG/PWR PLANE  (LAYER 3) | SECONDARY SIDE (LAYER 4) | SECONDARY SOLDER MASK | SECONDARY SILKSCREEN | SPECIFICATIONS: | ROHS COMPLIANCE NOTE: | MATERIALS; | MATERIAL FAMILY; | CLADDING; | SOLDER MASK; | SILK SCREEN; | SURFACE FINISH; | INTENTIONAL SHORTS; | TEST REQUIREMENTS; | 100% NETLIST ELECTRICAL VERIFICATION USING CUSTOMER | SUPPLIED IPC-D-356 NETLIST FOR OPENS AND SHORTS WHEN | "GERBER DATA" IS PROVIDED. THIS VERIFICATION ALSO | REQUIRED FOR "ODB++" DATA PER EMBEDDED NETLIST. | HOMOGENOUS MATERIALS IN THIS BOARD SHALL BE COMPLIANT | THE EU RoHS DIRECTIVE 2002/95/EC | ALL LAMINATES AND BONDING MATERIALS SHOULD BE SELECTED FROM | IPC-4101 OR IPC-4103, MINIMUM Tg>170degC, Td>300degC, | U.L. RATING OF 94 V-0 | ISOLA370HR OR S1000-2 OR IT180 OR EQUIVALENT. | EXTERNAL LAYERS .5 OZ. COPPER, OVERPLATE TO 1.5 OZ. | INTERNAL SIGNAL LAYERS .5 OZ. COPPER. | INTERNAL PLANE LAYERS 1 OZ. COPPER. | NOTE: IF THE LAYER STACKUP CONFLICTS WITH THE ABOVE | CLADDING SPECIFICATIONS THEN THE LAYER STACKUP SHALL | TAKE PRECEDENCE. | SHALL BE LIQUID PHOTOIMAGEABLE (LPI) APPLIED ON BOTH SIDES | OVER BARE COPPER OR GOLD AND SHALL MEET IPC-SM-840 | (LATEST REV.) CLASS 3. COLOR BLUE. | SHALL BE PERMANENT NON-CONDUCTIVE EPOXY INK, COLOR: WHITE | SYNTHETIC INKJET PRINTING ALLOWED FOR DENSE BOARDS, | COLOR: WHITE | ENIG (ELECTROLESS NICKEL/ IMMERSION GOLD) | PER IPC-4552 LATEST REVISION | IF SUPPLIED DATA INCLUDES A FILE "READ_ME.2", THEN | INTENTIONAL NET SHORTS EXIST. CUSTOMER REVIEW AND APPROVAL | IS REQUIRED IF SUPPLIED DATA REPORTS ANY CONDITION THAT | DOES NOT MATCH "READ_ME.2" FILE PROVIDED. | 15.    THRU VIAS FILLED WITH NON-CONDUCTIVE EPOXY AND PLATED OVER. | REQUIREMENTS: | 1.    REFER TO IPC-6010 SERIES (LATEST REV.), CLASS 2 FOR | FABRICATION UNLESS OTHERWISE SPECIFIED. | 2.    ACCEPTABILITY PER ANALOG DEVICES, INC. SPECIFICATION TST00115, | (LATEST REVISION.) | 3.    MODIFICATIONS TO THE ARTWORK ARE NOT ALLOWED WITHOUT | WRITTEN AUTHORIZATION. | 4.    HOLE PATTERN TOLERANCES FOR UNDIMENSIONED HOLES SHALL BE | A DIAMETER OF 0.005 INCHES FROM THEIR TRUE POSITION. | 5.    PLATED HOLE WALL THICKNESS SHALL NOT BE LESS THAN 0.001 INCH | MINIMUM AVERAGE, WITH NO READING LESS THAN .0008 INCH BY | CROSS SECTION. | 6.    HOLE DIAMETERS APPLY AFTER PLATING. | 7.    FINISHED CONDUCTOR WIDTHS SHALL NOT BE REDUCED FROM THE | NOMINAL INDICATED ON THE MASTER PATTERN, BY MORE THAN THE | CONDUCTOR THICKNESS. | 8.    MINIMUM DESIGN LINE WIDTH IS .004 INCH. | 9.    MINIMUM DESIGN SPACING IS .006 INCH. | 10.    NON-FUNCTIONAL PAD REMOVAL FROM INNER SIGNAL LAYERS MAY BE | PERFORMED AFTER CUSTOMER APPROVAL. | 11.    IF PAD SIZES PROVIDED ARE NOT LARGE ENOUGH TO MAINTAIN | ANNULAR RING REQUIREMENT, MFGR. MAY REQUEST APPROVAL TO | TEAR DROP PADS TO MAINTAIN ANNULAR RING. (AT PAD TO TRACE | INTERSECTION ONLY AND ELECTRICAL INTEGRITY MUST BE MAINTAINED.) | 12.    THIEVING MAY BE ADDED TO COMPENSATE FOR LOW COPPER DENSITY | AREAS ON THIS DESIGN ONLY AFTER REVIEW AND APPROVAL FROM | THE CUSTOMER: | A. THIEVING TO CARD EDGE, FIDUCIALS, NON-PLATED THROUGH HOLES, | ALL OTHER FEATURES TO BE 0.200 INCH MINIMUM. | B. THERE SHALL BE NO THIEVING IN ANY AREAS FREE OF SOLDER | MASK OR INTERNAL COPPER PLANES. | 13.    MFGR. TO LEGIBLY ETCH OR STAMP/SCREEN WITH PERMANENT | NON-CONDUCTIVE INK ON SECONDARY SIDE IN A CLEAR AREA | UNLESS OTHERWISE INDICATED; | A. U.L. CODE-FLAMMABILITY RATING   D. MFGR LOGO | B. DATE CODE (STAMP).              E. SUCCESSFUL ELECTRICAL TEST. | C. LOT NUMBER | 14.    REPAIRS PER IPC-7711/21 (LATEST REV.) ARE ALLOWED. | NOMINAL | FINISHED | THICKNESS | 0.062" +/-10% | 4 LAYER STACKUP
User.17: L2 GND | 08-      -07
User.18: L3 SIG/PWR | 08-      -08
User.45: FIGURE | SIZE | 6.0 | 8.0 | 40.0 | 45.0 | 50.0 | 26.0 | 55.0x24.0 | 67.0x24.0 | DRILL CHART: TOP to BOTTOM | FINISHED HOLES IN MILS | PLATED | NON-PLATED | QTY | 16 | 156 | 20 | 18 | 2 | TOLERANCE/NOTES
